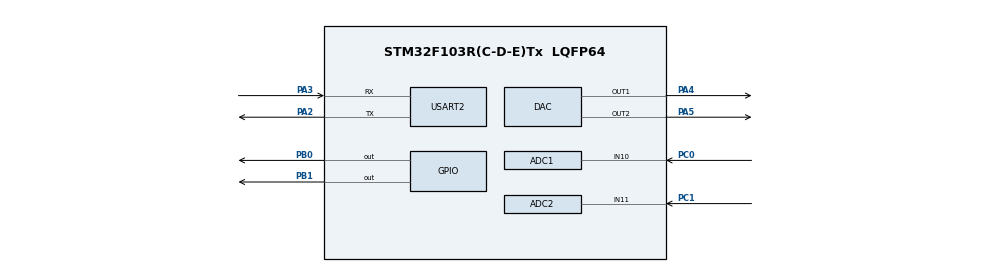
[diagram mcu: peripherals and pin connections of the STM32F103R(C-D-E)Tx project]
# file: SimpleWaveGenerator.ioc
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ADC1.Channel-1\#ChannelRegularConversion=ADC_CHANNEL_10
ADC1.NbrOfConversion=1
ADC1.NbrOfConversionFlag=1
ADC1.Rank-1\#ChannelRegularConversion=1
ADC1.SamplingTime-1\#ChannelRegularConversion=ADC_SAMPLETIME_55CYCLES_5
ADC1.master=1
ADC2.Channel-1\#ChannelRegularConversion=ADC_CHANNEL_11
ADC2.NbrOfConversionFlag=1
ADC2.Rank-1\#ChannelRegularConversion=1
ADC2.SamplingTime-1\#ChannelRegularConversion=ADC_SAMPLETIME_1CYCLE_5
Mcu.Family=STM32F1
Mcu.Name=STM32F103R(C-D-E)Tx
Mcu.Package=LQFP64
NVIC.PriorityGroup=NVIC_PRIORITYGROUP_4
NVIC.TIM1_UP_IRQn=true\:0\:0\:false\:false\:true\:true\:true\:true
PA13.Mode=Serial_Wire
PA13.Signal=SYS_JTMS-SWDIO
PA14.Mode=Serial_Wire
PA14.Signal=SYS_JTCK-SWCLK
PA2.Mode=Asynchronous
PA2.Signal=USART2_TX
PA3.Mode=Asynchronous
PA3.Signal=USART2_RX
PA4.Signal=COMP_DAC1_group
PA5.Signal=COMP_DAC2_group
PB0.GPIO_Speed=GPIO_SPEED_FREQ_HIGH
PB0.PinState=GPIO_PIN_SET
PB0.Signal=GPIO_Output
PB1.GPIO_Speed=GPIO_SPEED_FREQ_HIGH
PB1.PinState=GPIO_PIN_SET
PB1.Signal=GPIO_Output
PC0.Signal=ADCx_IN10
PC1.Signal=ADCx_IN11
PD0-OSC_IN.Mode=HSE-External-Oscillator
PD0-OSC_IN.Signal=RCC_OSC_IN
PD1-OSC_OUT.Mode=HSE-External-Oscillator
PD1-OSC_OUT.Signal=RCC_OSC_OUT
ProjectManager.HeapSize=0x200
ProjectManager.StackSize=0x400
ProjectManager.TargetToolchain=MDK-ARM V5.32
RCC.ADCPresc=RCC_ADCPCLK2_DIV6
RCC.AHBFreq_Value=72000000
RCC.APB1CLKDivider=RCC_HCLK_DIV2
RCC.APB1Freq_Value=36000000
RCC.APB1TimFreq_Value=72000000
RCC.APB2Freq_Value=72000000
RCC.APB2TimFreq_Value=72000000
RCC.HCLKFreq_Value=72000000
RCC.PLLMUL=RCC_PLL_MUL9
RCC.PLLSourceVirtual=RCC_PLLSOURCE_HSE
RCC.SYSCLKFreq_VALUE=72000000
RCC.SYSCLKSource=RCC_SYSCLKSOURCE_PLLCLK
RCC.USBFreq_Value=72000000
SH.ADCx_IN10.0=ADC1_IN10,IN10
SH.ADCx_IN11.0=ADC2_IN11,IN11
SH.COMP_DAC1_group.0=DAC_OUT1,DAC_OUT1
SH.COMP_DAC2_group.0=DAC_OUT2,DAC_OUT2
TIM1.AutoReloadPreload=TIM_AUTORELOAD_PRELOAD_ENABLE
TIM1.Period=10000
TIM1.Prescaler=71
USART2.VirtualMode=VM_ASYNC
VP_TIM1_VS_ClockSourceINT.Mode=Internal
board=custom

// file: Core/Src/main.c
/* USER CODE BEGIN Header */
/**
  ******************************************************************************
  * @file           : main.c
  * @brief          : Main program body
  ******************************************************************************
  * @attention
  *
  * Copyright (c) 2022 STMicroelectronics.
  * All rights reserved.
  *
  * This software is licensed under terms that can be found in the LICENSE file
  * in the root directory of this software component.
  * If no LICENSE file comes with this software, it is provided AS-IS.
  *
  ******************************************************************************
  */
/* USER CODE END Header */
#include "main.h"

 ADC_HandleTypeDef hadc1;
ADC_HandleTypeDef hadc2;

DAC_HandleTypeDef hdac;

TIM_HandleTypeDef htim1;

UART_HandleTypeDef huart2;

/* USER CODE BEGIN PV */
float sin_value[]={0.017,0.035,0.052,0.070,0.087,0.105,0.122,0.139,0.156,0.174,0.191,0.208,0.225,0.242,0.259,
									 0.276,0.292,0.309,0.326,0.342,0.358,0.375,0.391,0.407,0.423,0.438,0.454,0.469,0.485,0.500,
									 0.515,0.530,0.545,0.559,0.573,0.588,0.602,0.616,0.629,0.643,0.656,0.669,0.682,0.695,0.707,
									 0.719,0.731,0.743,0.755,0.766,0.777,0.788,0.799,0.809,0.819,0.829,0.839,0.848,0.857,0.866,
									 0.875,0.883,0.891,0.899,0.906,0.913,0.920,0.927,0.933,0.940,0.945,0.951,0.956,0.961,0.966,
									 0.970,0.974,0.978,0.982,0.985,0.988,0.990,0.993,0.994,0.996,0.998,0.999,0.999,1.000,1.000,
									 1.000,0.999,0.999,0.998,0.996,0.995,0.993,0.990,0.988,0.985,0.982,0.978,0.974,0.970,0.966,
	                 0.961,0.956,0.951,0.946,0.940,0.934,0.927,0.921,0.914,0.906,0.899,0.891,0.883,0.875,0.866,
	                 0.857,0.848,0.839,0.829,0.819,0.809,0.799,0.788,0.777,0.766,0.755,0.743,0.732,0.720,0.707,
	                 0.695,0.682,0.669,0.656,0.643,0.630,0.616,0.602,0.588,0.574,0.560,0.545,0.530,0.515,0.500,
	                 0.485,0.470,0.454,0.439,0.423,0.407,0.391,0.375,0.359,0.343,0.326,0.310,0.293,0.276,0.259,
	                 0.242,0.225,0.208,0.191,0.174,0.157,0.140,0.122,0.105,0.088,0.070,0.053,0.035,0.018,0.000};

//unsigned short delay_count = 9;//1020Hz
//unsigned short delay_count = 50;//444Hz
//unsigned short delay_count = 100;//263Hz
//unsigned short delay_count = 150;//187Hz
//unsigned short delay_count = 200;//145Hz
//unsigned short delay_count = 250;//118Hz

unsigned short delay_count = 785;
unsigned short lowest_40Hz = 785;
unsigned short highest_1000Hz = 9;

/*delay count*/
unsigned short freqlimit_1k_400[2] = {106,300};
unsigned short freqlimit_400_200[2]= {219,460};
unsigned short freqlimit_200_40[2] = {139,785};

/*sin wave table length*/
unsigned short table_length = 180;

/*look up for the table step up*/
unsigned short step_up[3] = {1,3,4};

/*amplitude*/
unsigned short amp = 2000;

/*offset*/
unsigned short offset = 2000;

unsigned short amplitude = 0;
unsigned short frequency = 0;
unsigned short frequency_step = 0;

/*important variable*/
unsigned short temp = 0;
float ADC_Value1_temp = 0;
float ADC_Value2_temp = 0;
unsigned short test_count = 0;

unsigned short ADC_Value1 = 0;
unsigned short ADC_Value2 = 0;

/* USER CODE END PV */

void SystemClock_Config(void);
static void MX_GPIO_Init(void);
static void MX_ADC1_Init(void);
static void MX_DAC_Init(void);
static void MX_USART2_UART_Init(void);
static void MX_ADC2_Init(void);
static void MX_TIM1_Init(void);
/* USER CODE BEGIN PFP */
void SysTick_Handler(void);
/* USER CODE END PFP */

/* USER CODE BEGIN 0 */
void output_sin_wave(unsigned short table_length, unsigned short step_gap, unsigned short delay_time, unsigned short amp, unsigned short offset)
{
		unsigned int output_value = 0;
		unsigned int count = 0;
	  unsigned short steps = 0;

		for(steps=0;steps<table_length;steps=steps+step_gap)
		{
			output_value = sin_value[steps]*amp+offset;
			for(count=0; count<delay_time; count++);
			HAL_DAC_SetValue(&hdac,DAC1_CHANNEL_1,DAC_ALIGN_12B_R,output_value);
		}

		for(steps=0;steps<table_length;steps=steps+step_gap)
		{
			output_value = -sin_value[steps]*amp+offset;
			for(count=0; count<delay_time; count++);
			HAL_DAC_SetValue(&hdac,DAC1_CHANNEL_1,DAC_ALIGN_12B_R,output_value);
		}
}

/* USER CODE END 0 */

int main(void)
{
  /* USER CODE BEGIN 1 */

	amplitude = 2000;
	frequency = 219;
	frequency_step = 6;

  /* USER CODE END 1 */

  /* MCU Configuration--------------------------------------------------------*/

  /* Reset of all peripherals, Initializes the Flash interface and the Systick. */
  HAL_Init();

  /* Configure the system clock */
  SystemClock_Config();

  /* Initialize all configured peripherals */
  MX_GPIO_Init();
  MX_ADC1_Init();
  MX_DAC_Init();
  MX_USART2_UART_Init();
  MX_ADC2_Init();
  MX_TIM1_Init();
  /* USER CODE BEGIN 2 */
	HAL_ADCEx_Calibration_Start(&hadc1);
	HAL_Delay(200);
	HAL_ADCEx_Calibration_Start(&hadc2);
	HAL_Delay(200);
	HAL_DAC_SetValue(&hdac,DAC1_CHANNEL_1,DAC_ALIGN_12B_R,0);
	HAL_DAC_SetValue(&hdac,DAC1_CHANNEL_2,DAC_ALIGN_12B_R,0);
	HAL_DAC_Start(&hdac,DAC1_CHANNEL_1);
	HAL_DAC_Start(&hdac,DAC1_CHANNEL_2);
	HAL_TIM_Base_Start_IT(&htim1);
  /* USER CODE END 2 */

  /* Infinite loop */
  while (1)
  {

    /* USER CODE BEGIN 3 */

//		if((count<=646) && (count>=0))
//		{
//			output_sin_wave(180, 1, 785-count, 2000, 2040);
//			count = count + 1;
//		}
//		else if(count>646 && count<=887)
//		{
//			temp = count - 646;
//			output_sin_wave(180, 3, 460-temp, 2000, 2040);
//			count = count + 1;
//		}
//		else if(count>887 && count<=1081)
//		{
//			temp = count - 887;
//			output_sin_wave(180, 4, 300-temp, 2000, 2040);
//			count = count + 1;
//		}
//		else if(count > 1081)
//		{
//			count = 0;
//		}

//		if(temp <= 2000)
//		{
			/* ADC_Value1--->Frequency  ADC_Value2--->Amplitude */
			output_sin_wave(table_length, frequency_step, ADC_Value1, ADC_Value2, offset);
//		}

//		else if(temp > 2000)
//		{
//			temp = 0;
//		}
//		temp = temp + 1;

  }
  /* USER CODE END 3 */
}

void SystemClock_Config(void)
{
  RCC_OscInitTypeDef RCC_OscInitStruct = {0};
  RCC_ClkInitTypeDef RCC_ClkInitStruct = {0};
  RCC_PeriphCLKInitTypeDef PeriphClkInit = {0};

  /** Initializes the RCC Oscillators according to the specified parameters
  * in the RCC_OscInitTypeDef structure.
  */
  RCC_OscInitStruct.OscillatorType = RCC_OSCILLATORTYPE_HSE;
  RCC_OscInitStruct.HSEState = RCC_HSE_ON;
  RCC_OscInitStruct.HSEPredivValue = RCC_HSE_PREDIV_DIV1;
  RCC_OscInitStruct.HSIState = RCC_HSI_ON;
  RCC_OscInitStruct.PLL.PLLState = RCC_PLL_ON;
  RCC_OscInitStruct.PLL.PLLSource = RCC_PLLSOURCE_HSE;
  RCC_OscInitStruct.PLL.PLLMUL = RCC_PLL_MUL12;
  if (HAL_RCC_OscConfig(&RCC_OscInitStruct) != HAL_OK)
  {
    Error_Handler();
  }

  /** Initializes the CPU, AHB and APB buses clocks
  */
  RCC_ClkInitStruct.ClockType = RCC_CLOCKTYPE_HCLK|RCC_CLOCKTYPE_SYSCLK
                              |RCC_CLOCKTYPE_PCLK1|RCC_CLOCKTYPE_PCLK2;
  RCC_ClkInitStruct.SYSCLKSource = RCC_SYSCLKSOURCE_PLLCLK;
  RCC_ClkInitStruct.AHBCLKDivider = RCC_SYSCLK_DIV1;
  RCC_ClkInitStruct.APB1CLKDivider = RCC_HCLK_DIV2;
  RCC_ClkInitStruct.APB2CLKDivider = RCC_HCLK_DIV1;

  if (HAL_RCC_ClockConfig(&RCC_ClkInitStruct, FLASH_LATENCY_2) != HAL_OK)
  {
    Error_Handler();
  }
  PeriphClkInit.PeriphClockSelection = RCC_PERIPHCLK_ADC;
  PeriphClkInit.AdcClockSelection = RCC_ADCPCLK2_DIV6;
  if (HAL_RCCEx_PeriphCLKConfig(&PeriphClkInit) != HAL_OK)
  {
    Error_Handler();
  }
}

static void MX_ADC1_Init(void)
{

  ADC_ChannelConfTypeDef sConfig = {0};

  /** Common config
  */
  hadc1.Instance = ADC1;
  hadc1.Init.ScanConvMode = ADC_SCAN_DISABLE;
  hadc1.Init.ContinuousConvMode = DISABLE;
  hadc1.Init.DiscontinuousConvMode = DISABLE;
  hadc1.Init.ExternalTrigConv = ADC_SOFTWARE_START;
  hadc1.Init.DataAlign = ADC_DATAALIGN_RIGHT;
  hadc1.Init.NbrOfConversion = 1;
  if (HAL_ADC_Init(&hadc1) != HAL_OK)
  {
    Error_Handler();
  }

  /** Configure Regular Channel
  */
  sConfig.Channel = ADC_CHANNEL_10;
  sConfig.Rank = ADC_REGULAR_RANK_1;
  sConfig.SamplingTime = ADC_SAMPLETIME_55CYCLES_5;
  if (HAL_ADC_ConfigChannel(&hadc1, &sConfig) != HAL_OK)
  {
    Error_Handler();
  }

}

static void MX_ADC2_Init(void)
{

  ADC_ChannelConfTypeDef sConfig = {0};

  /** Common config
  */
  hadc2.Instance = ADC2;
  hadc2.Init.ScanConvMode = ADC_SCAN_DISABLE;
  hadc2.Init.ContinuousConvMode = DISABLE;
  hadc2.Init.DiscontinuousConvMode = DISABLE;
  hadc2.Init.ExternalTrigConv = ADC_SOFTWARE_START;
  hadc2.Init.DataAlign = ADC_DATAALIGN_RIGHT;
  hadc2.Init.NbrOfConversion = 1;
  if (HAL_ADC_Init(&hadc2) != HAL_OK)
  {
    Error_Handler();
  }

  /** Configure Regular Channel
  */
  sConfig.Channel = ADC_CHANNEL_11;
  sConfig.Rank = ADC_REGULAR_RANK_1;
  sConfig.SamplingTime = ADC_SAMPLETIME_1CYCLE_5;
  if (HAL_ADC_ConfigChannel(&hadc2, &sConfig) != HAL_OK)
  {
    Error_Handler();
  }

}

static void MX_DAC_Init(void)
{

  DAC_ChannelConfTypeDef sConfig = {0};

  /** DAC Initialization
  */
  hdac.Instance = DAC;
  if (HAL_DAC_Init(&hdac) != HAL_OK)
  {
    Error_Handler();
  }

  /** DAC channel OUT1 config
  */
  sConfig.DAC_Trigger = DAC_TRIGGER_NONE;
  sConfig.DAC_OutputBuffer = DAC_OUTPUTBUFFER_ENABLE;
  if (HAL_DAC_ConfigChannel(&hdac, &sConfig, DAC_CHANNEL_1) != HAL_OK)
  {
    Error_Handler();
  }

  /** DAC channel OUT2 config
  */
  if (HAL_DAC_ConfigChannel(&hdac, &sConfig, DAC_CHANNEL_2) != HAL_OK)
  {
    Error_Handler();
  }

}

static void MX_TIM1_Init(void)
{

  TIM_ClockConfigTypeDef sClockSourceConfig = {0};
  TIM_MasterConfigTypeDef sMasterConfig = {0};

  htim1.Instance = TIM1;
  htim1.Init.Prescaler = 71;
  htim1.Init.CounterMode = TIM_COUNTERMODE_UP;
  htim1.Init.Period = 10000;
  htim1.Init.ClockDivision = TIM_CLOCKDIVISION_DIV1;
  htim1.Init.RepetitionCounter = 0;
  htim1.Init.AutoReloadPreload = TIM_AUTORELOAD_PRELOAD_ENABLE;
  if (HAL_TIM_Base_Init(&htim1) != HAL_OK)
  {
    Error_Handler();
  }
  sClockSourceConfig.ClockSource = TIM_CLOCKSOURCE_INTERNAL;
  if (HAL_TIM_ConfigClockSource(&htim1, &sClockSourceConfig) != HAL_OK)
  {
    Error_Handler();
  }
  sMasterConfig.MasterOutputTrigger = TIM_TRGO_RESET;
  sMasterConfig.MasterSlaveMode = TIM_MASTERSLAVEMODE_DISABLE;
  if (HAL_TIMEx_MasterConfigSynchronization(&htim1, &sMasterConfig) != HAL_OK)
  {
    Error_Handler();
  }
  /* USER CODE BEGIN TIM1_Init 2 */
	HAL_TIM_Base_Start_IT(&htim1);
  /* USER CODE END TIM1_Init 2 */

}

static void MX_USART2_UART_Init(void)
{

  huart2.Instance = USART2;
  huart2.Init.BaudRate = 115200;
  huart2.Init.WordLength = UART_WORDLENGTH_8B;
  huart2.Init.StopBits = UART_STOPBITS_1;
  huart2.Init.Parity = UART_PARITY_NONE;
  huart2.Init.Mode = UART_MODE_TX_RX;
  huart2.Init.HwFlowCtl = UART_HWCONTROL_NONE;
  huart2.Init.OverSampling = UART_OVERSAMPLING_16;
  if (HAL_UART_Init(&huart2) != HAL_OK)
  {
    Error_Handler();
  }

}

static void MX_GPIO_Init(void)
{
  GPIO_InitTypeDef GPIO_InitStruct = {0};

  /* GPIO Ports Clock Enable */
  __HAL_RCC_GPIOD_CLK_ENABLE();
  __HAL_RCC_GPIOC_CLK_ENABLE();
  __HAL_RCC_GPIOA_CLK_ENABLE();
  __HAL_RCC_GPIOB_CLK_ENABLE();

  /*Configure GPIO pin Output Level */
  HAL_GPIO_WritePin(GPIOB, GPIO_PIN_0|GPIO_PIN_1, GPIO_PIN_SET);

  /*Configure GPIO pins : PB0 PB1 */
  GPIO_InitStruct.Pin = GPIO_PIN_0|GPIO_PIN_1;
  GPIO_InitStruct.Mode = GPIO_MODE_OUTPUT_PP;
  GPIO_InitStruct.Pull = GPIO_NOPULL;
  GPIO_InitStruct.Speed = GPIO_SPEED_FREQ_HIGH;
  HAL_GPIO_Init(GPIOB, &GPIO_InitStruct);

}

/* USER CODE BEGIN 4 */

//void SysTick_Handler(void)
//{
//  systick_interrupt_disable();
//	systick_interrupt_flagclear();

//	HAL_ADC_Start(&hadc2);
//	HAL_ADC_PollForConversion(&hadc2,50);
//	ADC_Value2 = HAL_ADC_GetValue(&hadc2);
//
//	HAL_ADC_Start(&hadc1);
//	HAL_ADC_PollForConversion(&hadc1,50);
//	ADC_Value1 = HAL_ADC_GetValue(&hadc1);
//
//	test_count = test_count + 1;
//

//  systick_interrupt_enable();

//}

/* USER CODE END 4 */

void Error_Handler(void)
{
  __disable_irq();
  while (1)
  {
  }
}
